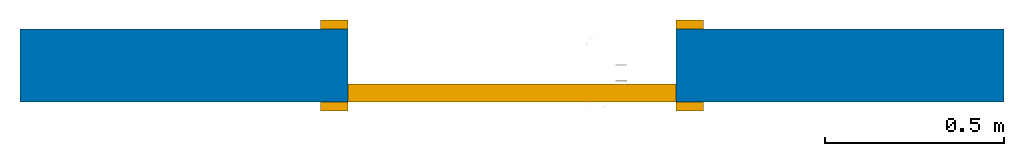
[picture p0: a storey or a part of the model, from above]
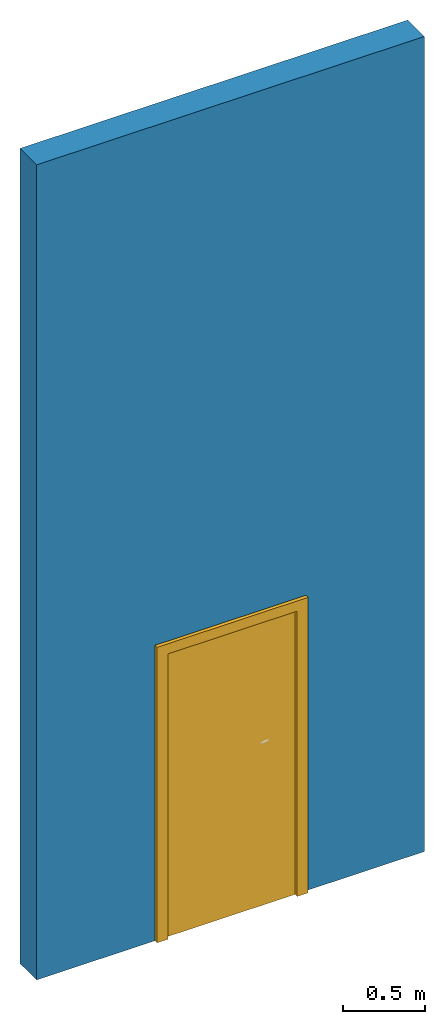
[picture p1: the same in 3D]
Properties of the parts of a building model (IFC2X3)

# File
Description: ViewDefinition [CoordinationView_V2.0]
File name: Project Number
Time: 2020-09-15T10:24:54
Written by: The EXPRESS Data Manager Version 5.02.0100.07 : 28 Aug 2013
Made in: 20190731_1515(x64) - Exporter 20.1.1.1 - Alternate UI 20.1.1.1
Comment: STEP Physical File produced by: The EXPRESS Data Manager Version 5.02.0100.07 : 28 Aug 2013 * Module: EDMstepFileFactory/EDMstandAlone * Creation date: Tue Sep 15 10:24:54 2020 * Host: LT-GBA1 * Database: C:\Users\gba\AppData\Local\Temp\b4dba12c-bb9b-4970-a707-02adad646c39\56ac3126-eed6-43b1-8659-ad0a99f1fbf0\ifc * Database version: 5507 * Database creation date: Tue Sep 15 10:24:49 2020 * Schema: IFC2X3 * Model: DataRepository.ifc * Model creation date: Tue Sep 15 10:24:49 2020 * Header model: DataRepository.ifc_HeaderModel * Header model creation date: Tue Sep 15 10:24:49 2020 * EDMuser: sdai-user * EDMgroup: sdai-group * License ID and type: 5605 : Permanent license. Expiry date: * EDMstepFileFactory options: 020000

# IfcProject, Project Number
LongName: Project Name; Phase: Project Status

# IfcSite, Default
RefLatitude: 42, 21, 31, 181945; RefLongitude: -71, -3, -24, -263305; RefElevation: 0 ft

# IfcBuilding
Pset_BuildingCommon - NumberOfStoreys: 1
Pset_ProductRequirements - Category: Project Information

# IfcBuildingStorey: Level:1/4" Head, Level 1
LongName: Level 1; Elevation: 0 ft
Pset_AirSideSystemInformation - Name: Level 1
Pset_ProductRequirements - Name: Level 1; Category: Levels

# IfcDoor: 36" x 84", Single-Flush:36" x 84":339219
In: Level 1
Type - OperationType: SINGLE_SWING_RIGHT; ParameterTakesPrecedence: no; Sizeable: no; Classification: C1020 Interior Doors (Uniformat); Material: Door - Frame, Door - Panel
Type - Single-Flush:36" x 84":339219 - PanelOperation: SWINGING
OverallHeight: 7 ft; OverallWidth: 3 ft
Pset_DoorCommon - IsExternal: no; Reference: 36" x 84"
Pset_ProductRequirements - Category: Doors
Pset_QuantityTakeOff - Reference: 36" x 84"

# IfcDoor: dline_Hardware_LeverHandles_AJ97_Brass_SolidRose_cc38_8x8mmSpindle_33-59mmThicknessDoors, 12404201038:dline_Hardware_LeverHandles_AJ97_Brass_SolidRose_cc38_8x8mmSpindle_33-59mmThicknessDoors:340235
In: Level 1
Type - ParameterTakesPrecedence: no; Sizeable: no; Material: Brass
OverallHeight: 0.66273 ft; OverallWidth: 0.406824 ft
Pset_ConcreteElementGeneral - FireRating: EN 1906 - B1: Suitable for use on fire/smoke door assemblies (tested with 200,000 test cycles on a test door)
Pset_DoorCommon - IsExternal: no; Reference: n/a; FireRating: EN 1906 - B1: Suitable for use on fire/smoke door assemblies (tested with 200,000 test cycles on a test door); AcousticRating: n/a; SecurityRating: EN 1906 - 0: Furniture not approved for use on burglary resistand doors; GlazingAreaFraction: 0; HandicapAccessible: no; FireExit: no; SelfClosing: no; SmokeStop: no
Pset_ElementShading - Color: Brass
Pset_ManufacturerOccurrence - BarCode: n/a; SerialNumber: n/a
Pset_ManufacturerTypeInformation - ModelReference: 45-25-60/315; Manufacturer: info@dline.com
Pset_PrecastConcreteElementGeneral - SerialNumber: n/a
Pset_ProductRequirements - Name: LeverHandles_AJ97_Brass_SolidRose_cc38_8x8mmSpindle_33-59mmThicknessDoors; Category: Doors
Pset_QuantityTakeOff - Reference: n/a

# IfcWallStandardCase: Basic Wall:Generic - 8", Basic Wall:Generic - 8":339175
In: Level 1
Type - PredefinedType: STANDARD; Material: Default Wall 0.666667 ft
Type - Pset_ElementShading - Roughness: 1 ft
Type - Pset_ProductRequirements - Category: Walls
Type - Pset_QuantityTakeOff - Reference: Generic - 8"
Type - Pset_ReinforcementBarPitchOfWall - Reference: Generic - 8"
Type - Pset_WallCommon - Reference: Generic - 8"; IsExternal: no
Classification: B2010 Exterior Walls (Uniformat)
Pset_QuantityTakeOff - sets with these values: 2
Pset_WallCommon - IsExternal: yes; ExtendToStructure: no; LoadBearing: no
